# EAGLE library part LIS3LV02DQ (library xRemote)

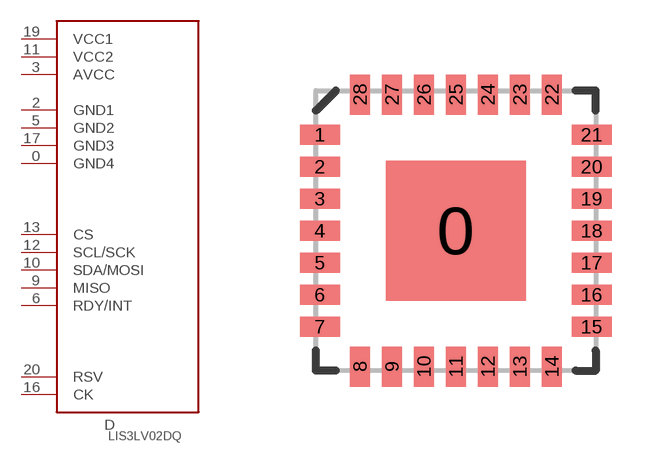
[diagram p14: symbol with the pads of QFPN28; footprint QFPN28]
Designator prefix D

## LIS3LV02DQ  [QFPN28]
0  GND4  sup
2  GND1  sup
3  AVCC  sup
5  GND2  sup
6  RDY/INT
9  MISO
10  SDA/MOSI
11  VCC2  sup
12  SCL/SCK
13  CS
16  CK
17  GND3  sup
19  VCC1  sup
20  RSV

## Footprint QFPN28 (pad centres in mm)
smd 3.5 x 3.5: 0 0,0
smd 1 x 0.5: 1 -3.4,2.4; 2 -3.4,1.6; 3 -3.4,0.8; 4 -3.4,0; 5 -3.4,-0.8; 6 -3.4,-1.6; 7 -3.4,-2.4; 15 3.4,-2.4; 16 3.4,-1.6; 17 3.4,-0.8; 18 3.4,0; 19 3.4,0.8; 20 3.4,1.6; 21 3.4,2.4
smd 0.5 x 1: 8 -2.4,-3.4; 9 -1.6,-3.4; 10 -0.8,-3.4; 11 0,-3.4; 12 0.8,-3.4; 13 1.6,-3.4; 14 2.4,-3.4; 22 2.4,3.4; 23 1.6,3.4; 24 0.8,3.4; 25 0,3.4; 26 -0.8,3.4; 27 -1.6,3.4; 28 -2.4,3.4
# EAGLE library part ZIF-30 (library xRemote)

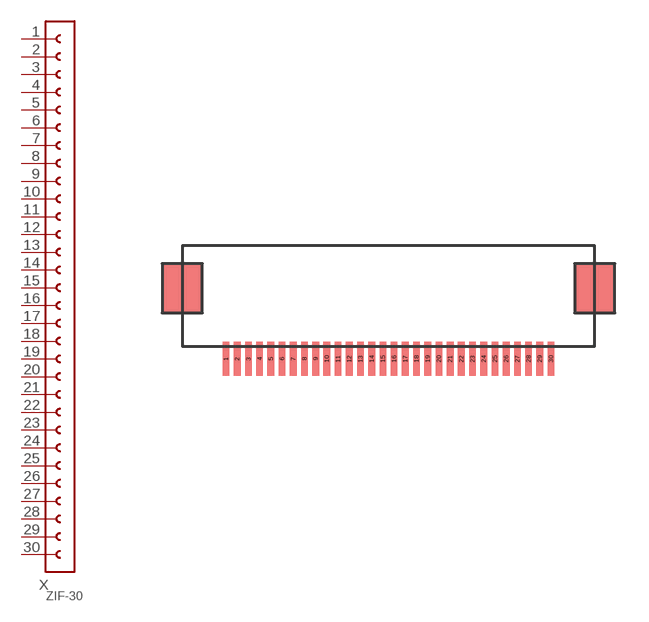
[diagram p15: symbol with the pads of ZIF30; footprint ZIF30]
Designator prefix X

## ZIF-30  [ZIF30]
1  P$1
2  P$2
3  P$3
4  P$4
5  P$5
6  P$6
7  P$7
8  P$8
9  P$9
10  P$10
11  P$11
12  P$12
13  P$13
14  P$14
15  P$15
16  P$16
17  P$17
18  P$18
19  P$19
20  P$20
21  P$21
22  P$22
23  P$23
24  P$24
25  P$25
26  P$26
27  P$27
28  P$28
29  P$29
30  P$30

## Footprint ZIF30 (pad centres in mm)
smd 0.3 x 1.5: 1 0.25,0.75; 2 0.75,0.75; 3 1.25,0.75; 4 1.75,0.75; 5 2.25,0.75; 6 2.75,0.75; 7 3.25,0.75; 8 3.75,0.75; 9 4.25,0.75; 10 4.75,0.75; 11 5.25,0.75; 12 5.75,0.75; 13 6.25,0.75; 14 6.75,0.75; 15 7.25,0.75; 16 7.75,0.75; 17 8.25,0.75; 18 8.75,0.75; 19 9.25,0.75; 20 9.75,0.75; 21 10.25,0.75; 22 10.75,0.75; 23 11.25,0.75; 24 11.75,0.75; 25 12.25,0.75; 26 12.75,0.75; 27 13.25,0.75; 28 13.75,0.75; 29 14.25,0.75; 30 14.75,0.75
